VERSION 5.8 ;
BUSBITCHARS "[]" ;
DIVIDERCHAR "/" ;
UNITS
  DATABASE MICRONS 1000 ;
END UNITS
LAYER M1
  TYPE ROUTING ;
  DIRECTION HORIZONTAL ;
  PITCH 0.2 ;
  WIDTH 0.1 ;
END M1
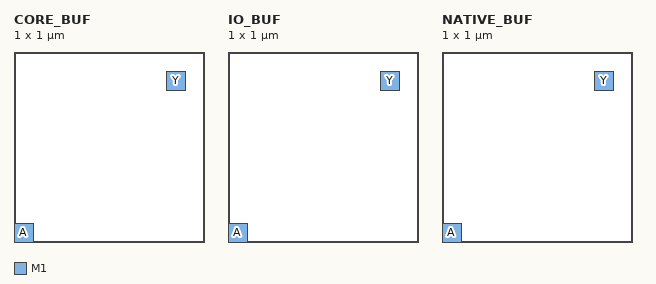
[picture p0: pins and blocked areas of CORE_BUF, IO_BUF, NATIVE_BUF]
MACRO CORE_BUF
  CLASS CORE ;
  ORIGIN 0 0 ;
  SIZE 1 BY 1 ;
  PIN A
    DIRECTION INPUT ;
    USE SIGNAL ;
    PORT
      LAYER M1 ;
      RECT 0.0 0.0 0.1 0.1 ;
    END
  END A
  PIN Y
    DIRECTION OUTPUT ;
    USE SIGNAL ;
    PORT
      LAYER M1 ;
      RECT 0.8 0.8 0.9 0.9 ;
    END
  END Y
END CORE_BUF
MACRO IO_BUF
  CLASS CORE ;
  ORIGIN 0 0 ;
  SIZE 1 BY 1 ;
  PIN A
    DIRECTION INPUT ;
    USE SIGNAL ;
    PORT
      LAYER M1 ;
      RECT 0.0 0.0 0.1 0.1 ;
    END
  END A
  PIN Y
    DIRECTION OUTPUT ;
    USE SIGNAL ;
    PORT
      LAYER M1 ;
      RECT 0.8 0.8 0.9 0.9 ;
    END
  END Y
END IO_BUF
MACRO NATIVE_BUF
  CLASS CORE ;
  ORIGIN 0 0 ;
  SIZE 1 BY 1 ;
  PIN A
    DIRECTION INPUT ;
    USE SIGNAL ;
    PORT
      LAYER M1 ;
      RECT 0.0 0.0 0.1 0.1 ;
    END
  END A
  PIN Y
    DIRECTION OUTPUT ;
    USE SIGNAL ;
    PORT
      LAYER M1 ;
      RECT 0.8 0.8 0.9 0.9 ;
    END
  END Y
END NATIVE_BUF
END LIBRARY
